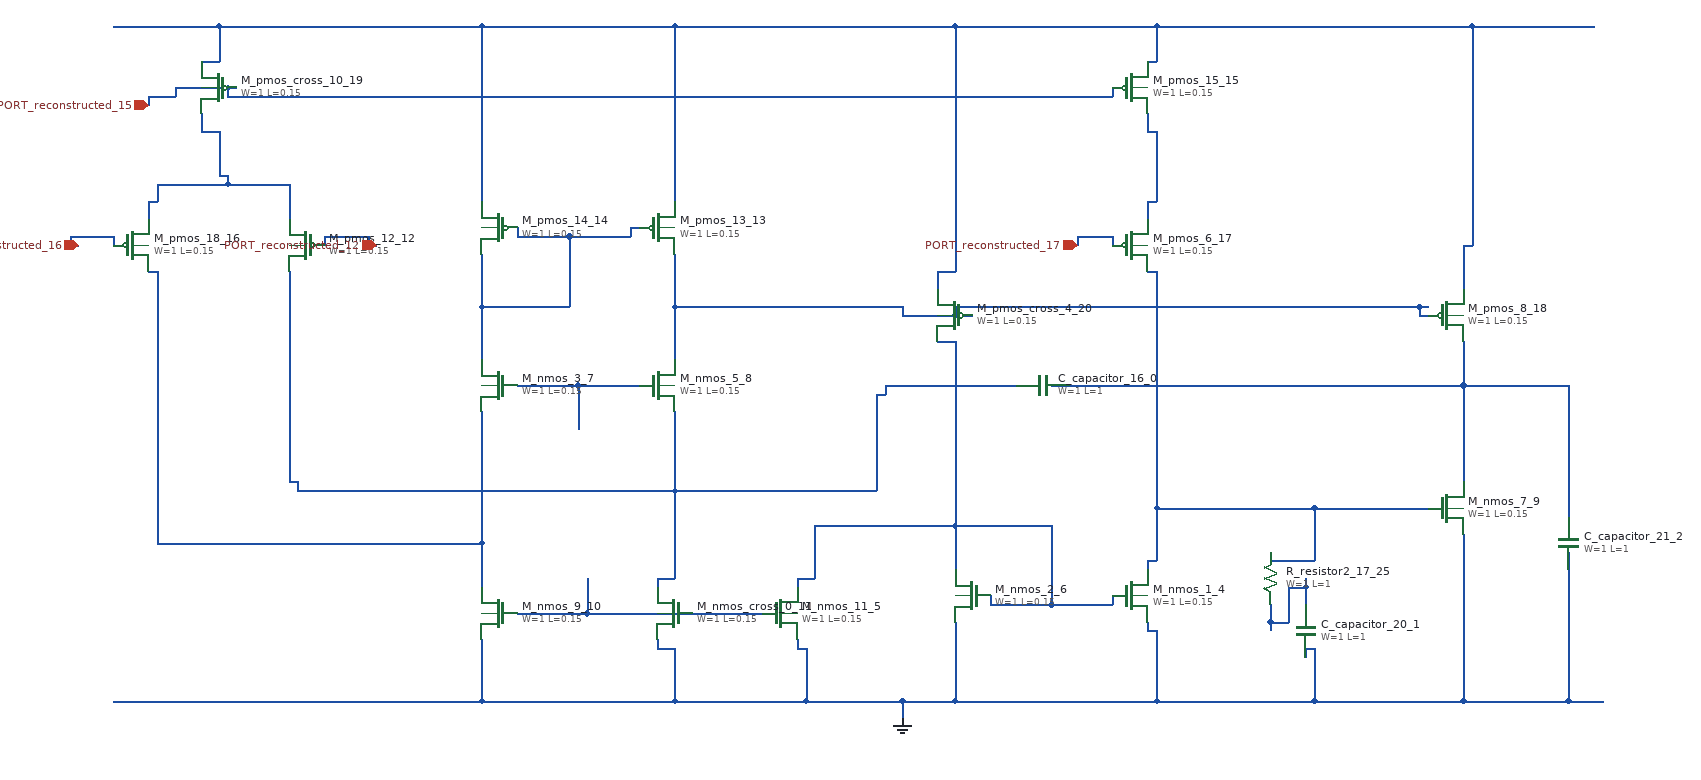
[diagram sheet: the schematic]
v {xschem version=3.4.8 file_version=1.2}
G {}
K {}
V {}
S {}
E {}
C {sky130_fd_pr/cap_mim_m3_1.sym} 1140 480 1 0 {name="C_capacitor_16_0" model=cap_mim_m3_1 W=1 L=1 MF=1 spiceprefix=X}
C {sky130_fd_pr/cap_mim_m3_1.sym} 1440 760 0 0 {name="C_capacitor_20_1" model=cap_mim_m3_1 W=1 L=1 MF=1 spiceprefix=X}
C {sky130_fd_pr/cap_mim_m3_1.sym} 1740 660 2 0 {name="C_capacitor_21_2" model=cap_mim_m3_1 W=1 L=1 MF=1 spiceprefix=X}
C {devices/gnd.sym} 980 860 0 0 {name="l_gnd_19_3" lab="GND"}
C {sky130_fd_pr/nfet3_01v8.sym} 1240 720 0 0 {name="M_nmos_1_4"
W=1
L=0.15
body=GND
nf=1
mult=1
ad="expr('int((@nf + 1)/2) * @W / @nf * 0.29')"
pd="expr('2*int((@nf + 1)/2) * (@W / @nf + 0.29)')"
as="expr('int((@nf + 2)/2) * @W / @nf * 0.29')"
ps="expr('2*int((@nf + 2)/2) * (@W / @nf + 0.29)')"
nrd="expr('0.29 / @W ')" nrs="expr('0.29 / @W ')"
sa=0 sb=0 sd=0
model=nfet_01v8
spiceprefix=X
}
C {sky130_fd_pr/nfet3_01v8.sym} 840 740 0 0 {name="M_nmos_11_5"
W=1
L=0.15
body=GND
nf=1
mult=1
ad="expr('int((@nf + 1)/2) * @W / @nf * 0.29')"
pd="expr('2*int((@nf + 1)/2) * (@W / @nf + 0.29)')"
as="expr('int((@nf + 2)/2) * @W / @nf * 0.29')"
ps="expr('2*int((@nf + 2)/2) * (@W / @nf + 0.29)')"
nrd="expr('0.29 / @W ')" nrs="expr('0.29 / @W ')"
sa=0 sb=0 sd=0
model=nfet_01v8
spiceprefix=X
}
C {sky130_fd_pr/nfet3_01v8.sym} 1060 720 0 1 {name="M_nmos_2_6"
W=1
L=0.15
body=GND
nf=1
mult=1
ad="expr('int((@nf + 1)/2) * @W / @nf * 0.29')"
pd="expr('2*int((@nf + 1)/2) * (@W / @nf + 0.29)')"
as="expr('int((@nf + 2)/2) * @W / @nf * 0.29')"
ps="expr('2*int((@nf + 2)/2) * (@W / @nf + 0.29)')"
nrd="expr('0.29 / @W ')" nrs="expr('0.29 / @W ')"
sa=0 sb=0 sd=0
model=nfet_01v8
spiceprefix=X
}
C {sky130_fd_pr/nfet3_01v8.sym} 520 480 0 1 {name="M_nmos_3_7"
W=1
L=0.15
body=GND
nf=1
mult=1
ad="expr('int((@nf + 1)/2) * @W / @nf * 0.29')"
pd="expr('2*int((@nf + 1)/2) * (@W / @nf + 0.29)')"
as="expr('int((@nf + 2)/2) * @W / @nf * 0.29')"
ps="expr('2*int((@nf + 2)/2) * (@W / @nf + 0.29)')"
nrd="expr('0.29 / @W ')" nrs="expr('0.29 / @W ')"
sa=0 sb=0 sd=0
model=nfet_01v8
spiceprefix=X
}
C {sky130_fd_pr/nfet3_01v8.sym} 700 480 0 0 {name="M_nmos_5_8"
W=1
L=0.15
body=GND
nf=1
mult=1
ad="expr('int((@nf + 1)/2) * @W / @nf * 0.29')"
pd="expr('2*int((@nf + 1)/2) * (@W / @nf + 0.29)')"
as="expr('int((@nf + 2)/2) * @W / @nf * 0.29')"
ps="expr('2*int((@nf + 2)/2) * (@W / @nf + 0.29)')"
nrd="expr('0.29 / @W ')" nrs="expr('0.29 / @W ')"
sa=0 sb=0 sd=0
model=nfet_01v8
spiceprefix=X
}
C {sky130_fd_pr/nfet3_01v8.sym} 1600 620 0 0 {name="M_nmos_7_9"
W=1
L=0.15
body=GND
nf=1
mult=1
ad="expr('int((@nf + 1)/2) * @W / @nf * 0.29')"
pd="expr('2*int((@nf + 1)/2) * (@W / @nf + 0.29)')"
as="expr('int((@nf + 2)/2) * @W / @nf * 0.29')"
ps="expr('2*int((@nf + 2)/2) * (@W / @nf + 0.29)')"
nrd="expr('0.29 / @W ')" nrs="expr('0.29 / @W ')"
sa=0 sb=0 sd=0
model=nfet_01v8
spiceprefix=X
}
C {sky130_fd_pr/nfet3_01v8.sym} 520 740 0 1 {name="M_nmos_9_10"
W=1
L=0.15
body=GND
nf=1
mult=1
ad="expr('int((@nf + 1)/2) * @W / @nf * 0.29')"
pd="expr('2*int((@nf + 1)/2) * (@W / @nf + 0.29)')"
as="expr('int((@nf + 2)/2) * @W / @nf * 0.29')"
ps="expr('2*int((@nf + 2)/2) * (@W / @nf + 0.29)')"
nrd="expr('0.29 / @W ')" nrs="expr('0.29 / @W ')"
sa=0 sb=0 sd=0
model=nfet_01v8
spiceprefix=X
}
C {sky130_fd_pr/nfet3_01v8.sym} 720 740 0 1 {name="M_nmos_cross_0_11"
W=1
L=0.15
body=GND
nf=1
mult=1
ad="expr('int((@nf + 1)/2) * @W / @nf * 0.29')"
pd="expr('2*int((@nf + 1)/2) * (@W / @nf + 0.29)')"
as="expr('int((@nf + 2)/2) * @W / @nf * 0.29')"
ps="expr('2*int((@nf + 2)/2) * (@W / @nf + 0.29)')"
nrd="expr('0.29 / @W ')" nrs="expr('0.29 / @W ')"
sa=0 sb=0 sd=0
model=nfet_01v8
spiceprefix=X
}
C {sky130_fd_pr/pfet3_01v8.sym} 300 320 0 1 {name="M_pmos_12_12"
W=1
L=0.15
body=VDD
nf=1
mult=1
ad="expr('int((@nf + 1)/2) * @W / @nf * 0.29')"
pd="expr('2*int((@nf + 1)/2) * (@W / @nf + 0.29)')"
as="expr('int((@nf + 2)/2) * @W / @nf * 0.29')"
ps="expr('2*int((@nf + 2)/2) * (@W / @nf + 0.29)')"
nrd="expr('0.29 / @W ')" nrs="expr('0.29 / @W ')"
sa=0 sb=0 sd=0
model=pfet_01v8
spiceprefix=X
}
C {sky130_fd_pr/pfet3_01v8.sym} 700 300 0 0 {name="M_pmos_13_13"
W=1
L=0.15
body=VDD
nf=1
mult=1
ad="expr('int((@nf + 1)/2) * @W / @nf * 0.29')"
pd="expr('2*int((@nf + 1)/2) * (@W / @nf + 0.29)')"
as="expr('int((@nf + 2)/2) * @W / @nf * 0.29')"
ps="expr('2*int((@nf + 2)/2) * (@W / @nf + 0.29)')"
nrd="expr('0.29 / @W ')" nrs="expr('0.29 / @W ')"
sa=0 sb=0 sd=0
model=pfet_01v8
spiceprefix=X
}
C {sky130_fd_pr/pfet3_01v8.sym} 520 300 0 1 {name="M_pmos_14_14"
W=1
L=0.15
body=VDD
nf=1
mult=1
ad="expr('int((@nf + 1)/2) * @W / @nf * 0.29')"
pd="expr('2*int((@nf + 1)/2) * (@W / @nf + 0.29)')"
as="expr('int((@nf + 2)/2) * @W / @nf * 0.29')"
ps="expr('2*int((@nf + 2)/2) * (@W / @nf + 0.29)')"
nrd="expr('0.29 / @W ')" nrs="expr('0.29 / @W ')"
sa=0 sb=0 sd=0
model=pfet_01v8
spiceprefix=X
}
C {sky130_fd_pr/pfet3_01v8.sym} 1240 140 0 0 {name="M_pmos_15_15"
W=1
L=0.15
body=VDD
nf=1
mult=1
ad="expr('int((@nf + 1)/2) * @W / @nf * 0.29')"
pd="expr('2*int((@nf + 1)/2) * (@W / @nf + 0.29)')"
as="expr('int((@nf + 2)/2) * @W / @nf * 0.29')"
ps="expr('2*int((@nf + 2)/2) * (@W / @nf + 0.29)')"
nrd="expr('0.29 / @W ')" nrs="expr('0.29 / @W ')"
sa=0 sb=0 sd=0
model=pfet_01v8
spiceprefix=X
}
C {sky130_fd_pr/pfet3_01v8.sym} 100 320 0 0 {name="M_pmos_18_16"
W=1
L=0.15
body=VDD
nf=1
mult=1
ad="expr('int((@nf + 1)/2) * @W / @nf * 0.29')"
pd="expr('2*int((@nf + 1)/2) * (@W / @nf + 0.29)')"
as="expr('int((@nf + 2)/2) * @W / @nf * 0.29')"
ps="expr('2*int((@nf + 2)/2) * (@W / @nf + 0.29)')"
nrd="expr('0.29 / @W ')" nrs="expr('0.29 / @W ')"
sa=0 sb=0 sd=0
model=pfet_01v8
spiceprefix=X
}
C {sky130_fd_pr/pfet3_01v8.sym} 1240 320 0 0 {name="M_pmos_6_17"
W=1
L=0.15
body=VDD
nf=1
mult=1
ad="expr('int((@nf + 1)/2) * @W / @nf * 0.29')"
pd="expr('2*int((@nf + 1)/2) * (@W / @nf + 0.29)')"
as="expr('int((@nf + 2)/2) * @W / @nf * 0.29')"
ps="expr('2*int((@nf + 2)/2) * (@W / @nf + 0.29)')"
nrd="expr('0.29 / @W ')" nrs="expr('0.29 / @W ')"
sa=0 sb=0 sd=0
model=pfet_01v8
spiceprefix=X
}
C {sky130_fd_pr/pfet3_01v8.sym} 1600 400 0 0 {name="M_pmos_8_18"
W=1
L=0.15
body=VDD
nf=1
mult=1
ad="expr('int((@nf + 1)/2) * @W / @nf * 0.29')"
pd="expr('2*int((@nf + 1)/2) * (@W / @nf + 0.29)')"
as="expr('int((@nf + 2)/2) * @W / @nf * 0.29')"
ps="expr('2*int((@nf + 2)/2) * (@W / @nf + 0.29)')"
nrd="expr('0.29 / @W ')" nrs="expr('0.29 / @W ')"
sa=0 sb=0 sd=0
model=pfet_01v8
spiceprefix=X
}
C {sky130_fd_pr/pfet3_01v8.sym} 200 140 0 1 {name="M_pmos_cross_10_19"
W=1
L=0.15
body=VDD
nf=1
mult=1
ad="expr('int((@nf + 1)/2) * @W / @nf * 0.29')"
pd="expr('2*int((@nf + 1)/2) * (@W / @nf + 0.29)')"
as="expr('int((@nf + 2)/2) * @W / @nf * 0.29')"
ps="expr('2*int((@nf + 2)/2) * (@W / @nf + 0.29)')"
nrd="expr('0.29 / @W ')" nrs="expr('0.29 / @W ')"
sa=0 sb=0 sd=0
model=pfet_01v8
spiceprefix=X
}
C {sky130_fd_pr/pfet3_01v8.sym} 1040 400 0 1 {name="M_pmos_cross_4_20"
W=1
L=0.15
body=VDD
nf=1
mult=1
ad="expr('int((@nf + 1)/2) * @W / @nf * 0.29')"
pd="expr('2*int((@nf + 1)/2) * (@W / @nf + 0.29)')"
as="expr('int((@nf + 2)/2) * @W / @nf * 0.29')"
ps="expr('2*int((@nf + 2)/2) * (@W / @nf + 0.29)')"
nrd="expr('0.29 / @W ')" nrs="expr('0.29 / @W ')"
sa=0 sb=0 sd=0
model=pfet_01v8
spiceprefix=X
}
C {devices/ipin.sym} 380 320 0 0 {name="p_port_22_21" lab="PORT_reconstructed_12"}
C {devices/ipin.sym} 40 320 0 0 {name="p_port_24_22" lab="PORT_reconstructed_16"}
C {devices/ipin.sym} 1180 320 0 0 {name="p_port_25_23" lab="PORT_reconstructed_17"}
C {devices/ipin.sym} 120 160 0 0 {name="p_port_26_24" lab="PORT_reconstructed_15"}
C {sky130_fd_pr/res_generic_po.sym} 1400 700 2 0 {name="R_resistor2_17_25"
W=1
L=1
model=res_generic_po
spiceprefix=X
mult=1}
N 700 700 720 700 {}
N 290 600 720 600 {}
N 720 600 950 600 {}
N 280 590 290 590 {}
N 950 490 960 490 {}
N 960 480 1110 480 {}
N 1110 480 1120 480 {}
N 280 590 280 350 {}
N 290 600 290 590 {}
N 700 710 700 700 {}
N 720 700 720 600 {}
N 720 600 720 510 {}
N 950 600 950 490 {}
N 960 490 960 480 {}
N 1150 480 1170 480 {}
N 1170 480 1620 480 {}
N 1620 480 1740 480 {}
N 1620 590 1620 480 {}
N 1620 480 1620 430 {}
N 1740 640 1740 630 {}
N 1740 630 1740 480 {}
N 1400 750 1420 750 {}
N 1420 710 1440 710 {}
N 1400 760 1400 750 {}
N 1400 750 1400 730 {}
N 1420 750 1420 710 {}
N 1440 730 1440 710 {}
N 1440 710 1440 700 {}
N 120 270 130 270 {}
N 130 250 210 250 {}
N 210 250 280 250 {}
N 200 240 210 240 {}
N 180 190 200 190 {}
N 120 290 120 270 {}
N 130 270 130 250 {}
N 180 190 180 170 {}
N 200 240 200 190 {}
N 210 250 210 240 {}
N 280 290 280 250 {}
N 370 320 380 320 {}
N 320 310 370 310 {}
N 320 320 320 310 {}
N 370 320 370 310 {}
N 1020 350 1040 350 {}
N 1620 320 1630 320 {}
N 180 110 200 110 {}
N 1260 110 1270 110 {}
N 80 70 200 70 {}
N 200 70 500 70 {}
N 500 70 720 70 {}
N 720 70 1040 70 {}
N 1040 70 1270 70 {}
N 1270 70 1630 70 {}
N 1630 70 1770 70 {}
N 200 110 200 70 {}
N 500 270 500 70 {}
N 720 270 720 70 {}
N 1020 370 1020 350 {}
N 1040 350 1040 70 {}
N 1270 110 1270 70 {}
N 1620 370 1620 320 {}
N 1630 320 1630 70 {}
N 1260 270 1270 270 {}
N 1260 190 1270 190 {}
N 1260 290 1260 270 {}
N 1260 190 1260 170 {}
N 1270 270 1270 190 {}
N 120 150 150 150 {}
N 210 150 1220 150 {}
N 150 140 210 140 {}
N 210 140 220 140 {}
N 120 160 120 150 {}
N 150 150 150 140 {}
N 210 150 210 140 {}
N 1220 150 1220 140 {}
N 30 320 40 320 {}
N 30 310 80 310 {}
N 30 320 30 310 {}
N 80 320 80 310 {}
N 1180 310 1220 310 {}
N 1180 320 1180 310 {}
N 1220 320 1220 310 {}
N 1080 730 1150 730 {}
N 1150 730 1220 730 {}
N 860 700 880 700 {}
N 880 640 1040 640 {}
N 1040 640 1150 640 {}
N 1020 430 1040 430 {}
N 860 710 860 700 {}
N 880 700 880 640 {}
N 1040 690 1040 640 {}
N 1040 640 1040 430 {}
N 1080 730 1080 720 {}
N 1150 730 1150 640 {}
N 1220 730 1220 720 {}
N 80 840 500 840 {}
N 500 840 720 840 {}
N 720 840 870 840 {}
N 870 840 980 840 {}
N 980 840 1040 840 {}
N 1040 840 1270 840 {}
N 1270 840 1450 840 {}
N 1450 840 1620 840 {}
N 1620 840 1740 840 {}
N 1740 840 1780 840 {}
N 700 780 720 780 {}
N 860 780 870 780 {}
N 1440 780 1450 780 {}
N 1260 760 1270 760 {}
N 500 840 500 770 {}
N 700 780 700 770 {}
N 720 840 720 780 {}
N 860 780 860 770 {}
N 870 840 870 780 {}
N 980 860 980 840 {}
N 1040 840 1040 750 {}
N 1260 760 1260 750 {}
N 1270 840 1270 760 {}
N 1440 790 1440 780 {}
N 1450 840 1450 780 {}
N 1620 840 1620 650 {}
N 1740 840 1740 690 {}
N 1740 690 1740 670 {}
N 540 740 620 740 {}
N 620 740 740 740 {}
N 740 740 820 740 {}
N 820 740 830 740 {}
N 620 740 620 700 {}
N 130 660 500 660 {}
N 120 350 130 350 {}
N 130 660 130 350 {}
N 500 710 500 660 {}
N 500 660 500 510 {}
N 500 390 600 390 {}
N 540 310 600 310 {}
N 600 310 670 310 {}
N 670 300 680 300 {}
N 500 450 500 390 {}
N 500 390 500 330 {}
N 540 310 540 300 {}
N 600 390 600 310 {}
N 670 310 670 300 {}
N 540 480 610 480 {}
N 610 480 680 480 {}
N 610 530 610 480 {}
N 980 400 1040 400 {}
N 1040 400 1060 400 {}
N 1570 400 1580 400 {}
N 720 390 980 390 {}
N 1040 390 1570 390 {}
N 1570 390 1580 390 {}
N 720 450 720 390 {}
N 720 390 720 330 {}
N 980 400 980 390 {}
N 1040 400 1040 390 {}
N 1570 400 1570 390 {}
N 1260 680 1270 680 {}
N 1400 680 1450 680 {}
N 1270 620 1450 620 {}
N 1450 620 1580 620 {}
N 1260 350 1270 350 {}
N 1260 690 1260 680 {}
N 1270 680 1270 620 {}
N 1270 620 1270 350 {}
N 1400 680 1400 670 {}
N 1450 680 1450 620 {}
